VERSION 5.7 ;
  NOWIREEXTENSIONATPIN ON ;
  DIVIDERCHAR "/" ;
  BUSBITCHARS "[]" ;
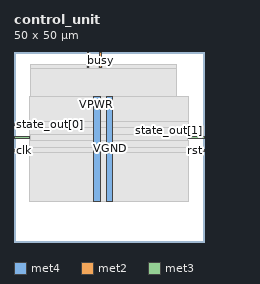
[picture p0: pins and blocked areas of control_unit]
MACRO control_unit
  CLASS BLOCK ;
  FOREIGN control_unit ;
  ORIGIN 0.000 0.000 ;
  SIZE 50.000 BY 50.000 ;
  PIN VGND
    DIRECTION INOUT ;
    USE GROUND ;
    PORT
      LAYER met4 ;
        RECT 24.340 10.640 25.940 38.320 ;
    END
  END VGND
  PIN VPWR
    DIRECTION INOUT ;
    USE POWER ;
    PORT
      LAYER met4 ;
        RECT 21.040 10.640 22.640 38.320 ;
    END
  END VPWR
  PIN busy
    DIRECTION OUTPUT ;
    USE SIGNAL ;
    ANTENNADIFFAREA 0.445500 ;
    PORT
      LAYER met2 ;
        RECT 22.630 46.000 22.910 50.000 ;
    END
  END busy
  PIN clk
    DIRECTION INPUT ;
    USE SIGNAL ;
    ANTENNAGATEAREA 0.852000 ;
    PORT
      LAYER met3 ;
        RECT 0.000 23.840 4.000 24.440 ;
    END
  END clk
  PIN done
    DIRECTION OUTPUT ;
    USE SIGNAL ;
    ANTENNADIFFAREA 0.445500 ;
    PORT
      LAYER met2 ;
        RECT 19.410 46.000 19.690 50.000 ;
    END
  END done
  PIN rst
    DIRECTION INPUT ;
    USE SIGNAL ;
    ANTENNAGATEAREA 0.196500 ;
    PORT
      LAYER met3 ;
        RECT 46.000 23.840 50.000 24.440 ;
    END
  END rst
  PIN start
    DIRECTION INPUT ;
    USE SIGNAL ;
    ANTENNAGATEAREA 0.196500 ;
    PORT
      LAYER met3 ;
        RECT 0.000 27.240 4.000 27.840 ;
    END
  END start
  PIN state_out[0]
    DIRECTION OUTPUT ;
    USE SIGNAL ;
    ANTENNADIFFAREA 0.445500 ;
    PORT
      LAYER met3 ;
        RECT 0.000 30.640 4.000 31.240 ;
    END
  END state_out[0]
  PIN state_out[1]
    DIRECTION OUTPUT ;
    USE SIGNAL ;
    ANTENNADIFFAREA 0.445500 ;
    PORT
      LAYER met3 ;
        RECT 46.000 27.240 50.000 27.840 ;
    END
  END state_out[1]
  OBS
      LAYER nwell ;
        RECT 5.330 10.795 44.350 38.165 ;
      LAYER li1 ;
        RECT 5.520 10.795 44.160 38.165 ;
      LAYER met1 ;
        RECT 4.210 10.640 44.160 38.320 ;
      LAYER met2 ;
        RECT 4.230 45.720 19.130 46.650 ;
        RECT 19.970 45.720 22.350 46.650 ;
        RECT 23.190 45.720 42.690 46.650 ;
        RECT 4.230 10.695 42.690 45.720 ;
      LAYER met3 ;
        RECT 3.990 31.640 46.000 38.245 ;
        RECT 4.400 30.240 46.000 31.640 ;
        RECT 3.990 28.240 46.000 30.240 ;
        RECT 4.400 26.840 45.600 28.240 ;
        RECT 3.990 24.840 46.000 26.840 ;
        RECT 4.400 23.440 45.600 24.840 ;
        RECT 3.990 10.715 46.000 23.440 ;
  END
END control_unit
END LIBRARY

